VERSION 5.7 ;
  NOWIREEXTENSIONATPIN ON ;
  DIVIDERCHAR "/" ;
  BUSBITCHARS "[]" ;
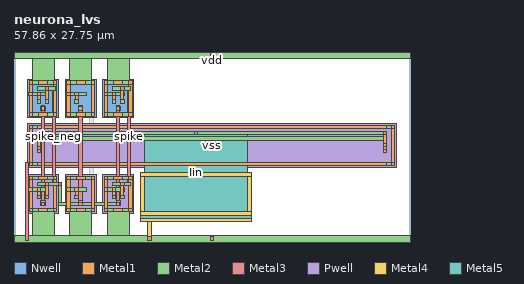
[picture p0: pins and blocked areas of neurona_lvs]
MACRO neurona_lvs
  CLASS BLOCK ;
  FOREIGN neurona_lvs ;
  ORIGIN 2.000 4.200 ;
  SIZE 57.860 BY 27.750 ;
  PIN vdd
    ANTENNADIFFAREA 18.719999 ;
    PORT
      LAYER Nwell ;
        RECT 0.000 13.950 4.490 19.550 ;
        RECT 5.490 13.950 9.980 19.550 ;
        RECT 10.980 13.950 15.470 19.550 ;
      LAYER Metal1 ;
        RECT 0.230 18.840 0.730 19.340 ;
        RECT 1.595 18.840 2.895 19.340 ;
        RECT 3.760 18.840 4.260 19.340 ;
        RECT 0.230 17.645 0.690 18.840 ;
        RECT 0.190 17.145 0.690 17.645 ;
        RECT 1.400 17.145 1.900 17.645 ;
        RECT 0.230 14.660 0.690 17.145 ;
        RECT 1.420 16.595 1.880 17.145 ;
        RECT 1.400 16.095 1.900 16.595 ;
        RECT 3.800 14.660 4.260 18.840 ;
        RECT 5.720 18.840 6.220 19.340 ;
        RECT 7.085 18.840 8.385 19.340 ;
        RECT 9.250 18.840 9.750 19.340 ;
        RECT 5.720 17.645 6.180 18.840 ;
        RECT 5.680 17.145 6.180 17.645 ;
        RECT 6.890 17.145 7.390 17.645 ;
        RECT 0.230 14.160 0.730 14.660 ;
        RECT 1.595 14.160 2.895 14.660 ;
        RECT 3.760 14.160 4.260 14.660 ;
        RECT 5.720 14.660 6.180 17.145 ;
        RECT 6.910 16.595 7.370 17.145 ;
        RECT 6.890 16.095 7.390 16.595 ;
        RECT 9.290 14.660 9.750 18.840 ;
        RECT 11.210 18.840 11.710 19.340 ;
        RECT 12.575 18.840 13.875 19.340 ;
        RECT 14.740 18.840 15.240 19.340 ;
        RECT 11.210 17.645 11.670 18.840 ;
        RECT 11.170 17.145 11.670 17.645 ;
        RECT 12.380 17.145 12.880 17.645 ;
        RECT 5.720 14.160 6.220 14.660 ;
        RECT 7.085 14.160 8.385 14.660 ;
        RECT 9.250 14.160 9.750 14.660 ;
        RECT 11.210 14.660 11.670 17.145 ;
        RECT 12.400 16.595 12.860 17.145 ;
        RECT 12.380 16.095 12.880 16.595 ;
        RECT 14.780 14.660 15.240 18.840 ;
        RECT 11.210 14.160 11.710 14.660 ;
        RECT 12.575 14.160 13.875 14.660 ;
        RECT 14.740 14.160 15.240 14.660 ;
      LAYER Metal2 ;
        RECT -2.000 22.550 55.860 23.550 ;
        RECT 0.640 19.340 3.850 22.550 ;
        RECT 6.130 19.340 9.340 22.550 ;
        RECT 11.620 19.340 14.830 22.550 ;
        RECT 0.230 18.840 4.260 19.340 ;
        RECT 5.720 18.840 9.750 19.340 ;
        RECT 11.210 18.840 15.240 19.340 ;
        RECT 0.190 17.145 3.090 17.645 ;
        RECT 5.680 17.145 8.580 17.645 ;
        RECT 11.170 17.145 14.070 17.645 ;
        RECT 1.400 16.095 1.900 16.595 ;
        RECT 6.890 16.095 7.390 16.595 ;
        RECT 12.380 16.095 12.880 16.595 ;
        RECT 0.230 14.160 4.260 14.660 ;
        RECT 5.720 14.160 9.750 14.660 ;
        RECT 11.210 14.160 15.240 14.660 ;
      LAYER Metal3 ;
        RECT 26.680 22.800 27.180 23.300 ;
    END
  END vdd
  PIN vss
    ANTENNADIFFAREA 61.496399 ;
    PORT
      LAYER Pwell ;
        RECT 0.000 6.725 53.860 13.075 ;
        RECT 0.000 0.000 4.490 5.600 ;
        RECT 5.490 0.000 9.980 5.600 ;
        RECT 10.980 0.000 15.470 5.600 ;
      LAYER Metal1 ;
        RECT 0.230 12.365 0.730 12.865 ;
        RECT 1.480 12.365 52.380 12.865 ;
        RECT 53.130 12.365 53.630 12.865 ;
        RECT 0.230 11.175 0.690 12.365 ;
        RECT 0.190 10.675 0.690 11.175 ;
        RECT 1.400 10.675 1.900 11.175 ;
        RECT 0.230 7.435 0.690 10.675 ;
        RECT 1.420 9.750 1.880 10.675 ;
        RECT 1.400 9.250 1.900 9.750 ;
        RECT 1.420 8.875 1.880 9.250 ;
        RECT 53.170 7.435 53.630 12.365 ;
        RECT 0.230 6.935 0.730 7.435 ;
        RECT 1.480 6.935 52.380 7.435 ;
        RECT 53.130 6.935 53.630 7.435 ;
        RECT 0.230 4.890 0.730 5.390 ;
        RECT 1.595 4.890 2.895 5.390 ;
        RECT 3.760 4.890 4.260 5.390 ;
        RECT 0.230 3.695 0.690 4.890 ;
        RECT 0.190 3.195 0.690 3.695 ;
        RECT 1.400 3.195 1.900 3.695 ;
        RECT 0.230 0.710 0.690 3.195 ;
        RECT 1.420 2.645 1.880 3.195 ;
        RECT 1.400 2.145 1.900 2.645 ;
        RECT 3.800 0.710 4.260 4.890 ;
        RECT 5.720 4.890 6.220 5.390 ;
        RECT 7.085 4.890 8.385 5.390 ;
        RECT 9.250 4.890 9.750 5.390 ;
        RECT 5.720 3.695 6.180 4.890 ;
        RECT 5.680 3.195 6.180 3.695 ;
        RECT 6.890 3.195 7.390 3.695 ;
        RECT 0.230 0.210 0.730 0.710 ;
        RECT 1.595 0.210 2.895 0.710 ;
        RECT 3.760 0.210 4.260 0.710 ;
        RECT 5.720 0.710 6.180 3.195 ;
        RECT 6.910 2.645 7.370 3.195 ;
        RECT 6.890 2.145 7.390 2.645 ;
        RECT 9.290 0.710 9.750 4.890 ;
        RECT 11.210 4.890 11.710 5.390 ;
        RECT 12.575 4.890 13.875 5.390 ;
        RECT 14.740 4.890 15.240 5.390 ;
        RECT 11.210 3.695 11.670 4.890 ;
        RECT 11.170 3.195 11.670 3.695 ;
        RECT 12.380 3.195 12.880 3.695 ;
        RECT 5.720 0.210 6.220 0.710 ;
        RECT 7.085 0.210 8.385 0.710 ;
        RECT 9.250 0.210 9.750 0.710 ;
        RECT 11.210 0.710 11.670 3.195 ;
        RECT 12.400 2.645 12.860 3.195 ;
        RECT 12.380 2.145 12.880 2.645 ;
        RECT 14.780 0.710 15.240 4.890 ;
        RECT 11.210 0.210 11.710 0.710 ;
        RECT 12.575 0.210 13.875 0.710 ;
        RECT 14.740 0.210 15.240 0.710 ;
      LAYER Metal2 ;
        RECT 0.230 12.365 53.630 12.865 ;
        RECT 0.190 10.675 52.460 11.175 ;
        RECT 1.400 8.875 1.900 10.125 ;
        RECT -0.360 6.935 53.630 7.435 ;
        RECT 0.230 4.890 4.260 5.390 ;
        RECT 5.720 4.890 9.750 5.390 ;
        RECT 11.210 4.890 15.240 5.390 ;
        RECT 0.190 3.195 3.090 3.695 ;
        RECT 5.680 3.195 8.580 3.695 ;
        RECT 11.170 3.195 14.070 3.695 ;
        RECT 1.400 2.145 1.900 2.645 ;
        RECT 6.890 2.145 7.390 2.645 ;
        RECT 12.380 2.145 12.880 2.645 ;
        RECT 0.230 0.210 4.260 0.710 ;
        RECT 5.720 0.210 9.750 0.710 ;
        RECT 11.210 0.210 15.240 0.710 ;
        RECT 0.640 -3.200 3.850 0.210 ;
        RECT 6.130 -3.200 9.340 0.210 ;
        RECT 11.620 -3.200 14.830 0.210 ;
        RECT -2.000 -4.200 55.860 -3.200 ;
      LAYER Metal3 ;
        RECT -0.360 -3.950 0.140 7.435 ;
        RECT 17.520 -3.950 18.020 -3.450 ;
        RECT 26.680 -3.950 27.180 -3.450 ;
      LAYER Metal4 ;
        RECT 16.470 5.300 32.670 5.900 ;
        RECT 16.470 0.300 17.070 5.300 ;
        RECT 32.070 0.300 32.670 5.300 ;
        RECT 16.470 -1.200 32.670 0.300 ;
        RECT 17.520 -3.950 18.020 -1.200 ;
      LAYER Metal5 ;
        RECT 16.470 -0.800 32.670 -0.300 ;
    END
  END vss
  PIN spike
    ANTENNADIFFAREA 0.600000 ;
    PORT
      LAYER Metal1 ;
        RECT 13.570 17.945 14.070 18.445 ;
        RECT 13.590 16.595 14.050 17.945 ;
        RECT 13.570 16.095 14.070 16.595 ;
        RECT 13.570 3.995 14.070 4.495 ;
        RECT 13.590 2.645 14.050 3.995 ;
        RECT 13.570 2.145 14.070 2.645 ;
      LAYER Metal2 ;
        RECT 12.380 17.945 15.070 18.445 ;
        RECT 13.570 16.095 14.070 16.595 ;
        RECT 12.380 3.995 15.070 4.495 ;
        RECT 13.570 2.145 14.070 2.645 ;
      LAYER Metal3 ;
        RECT 13.570 17.945 14.070 18.445 ;
        RECT 14.570 3.995 15.070 18.445 ;
    END
  END spike
  PIN spike_neg
    ANTENNAGATEAREA 1.260000 ;
    ANTENNADIFFAREA 0.600000 ;
    PORT
      LAYER Metal1 ;
        RECT 2.590 17.945 3.090 18.445 ;
        RECT 2.610 16.595 3.070 17.945 ;
        RECT 2.590 16.095 3.090 16.595 ;
        RECT 7.485 15.055 7.985 15.555 ;
        RECT 12.975 15.055 13.475 15.555 ;
        RECT 2.590 3.995 3.090 4.495 ;
        RECT 2.610 2.645 3.070 3.995 ;
        RECT 2.590 2.145 3.090 2.645 ;
        RECT 7.485 1.105 7.985 1.605 ;
        RECT 12.975 1.105 13.475 1.605 ;
      LAYER Metal2 ;
        RECT 1.400 17.945 4.090 18.445 ;
        RECT 2.590 16.095 3.090 16.595 ;
        RECT 7.485 15.555 7.985 15.805 ;
        RECT 12.975 15.555 13.475 15.805 ;
        RECT 7.420 15.055 8.050 15.555 ;
        RECT 12.910 15.055 13.540 15.555 ;
        RECT 1.400 3.995 4.940 4.495 ;
        RECT 2.590 2.145 3.090 2.645 ;
        RECT 4.440 1.605 4.940 3.995 ;
        RECT 7.420 1.605 8.050 1.855 ;
        RECT 12.910 1.605 13.540 1.855 ;
        RECT 4.440 1.105 13.540 1.605 ;
      LAYER Metal3 ;
        RECT 2.590 17.945 3.090 18.445 ;
        RECT 3.590 3.995 4.090 18.445 ;
        RECT 4.440 3.995 4.940 4.495 ;
        RECT 7.485 1.355 7.985 15.805 ;
        RECT 12.975 1.355 13.475 15.805 ;
    END
  END spike_neg
  PIN Iin
    ANTENNAGATEAREA 0.630000 ;
    ANTENNADIFFAREA 0.750000 ;
    PORT
      LAYER Metal1 ;
        RECT 1.995 15.055 2.495 15.555 ;
        RECT 51.960 11.475 52.460 11.975 ;
        RECT 51.980 9.750 52.440 11.475 ;
        RECT 51.960 9.250 52.460 9.750 ;
        RECT 51.980 8.875 52.440 9.250 ;
        RECT 1.995 1.105 2.495 1.605 ;
      LAYER Metal2 ;
        RECT 1.995 15.555 2.495 15.805 ;
        RECT 1.930 15.055 2.560 15.555 ;
        RECT 1.995 11.975 2.495 12.005 ;
        RECT 1.400 11.475 52.460 11.975 ;
        RECT 51.960 8.875 52.460 10.125 ;
        RECT 1.930 1.105 2.560 1.855 ;
      LAYER Metal3 ;
        RECT 1.995 1.355 2.495 15.805 ;
        RECT 24.320 11.475 24.820 11.975 ;
        RECT 51.960 11.475 52.460 11.975 ;
      LAYER Metal4 ;
        RECT 24.320 11.475 24.820 11.975 ;
      LAYER Metal5 ;
        RECT 24.320 11.475 24.820 11.975 ;
        RECT 17.070 0.300 32.070 11.475 ;
    END
  END Iin
  OBS
      LAYER Metal1 ;
        RECT 8.080 17.945 8.580 18.445 ;
        RECT 8.100 16.595 8.560 17.945 ;
        RECT 8.080 16.095 8.580 16.595 ;
        RECT 2.280 7.830 2.780 8.330 ;
        RECT 3.080 7.830 3.580 8.330 ;
        RECT 3.880 7.830 4.380 8.330 ;
        RECT 4.680 7.830 5.180 8.330 ;
        RECT 5.480 7.830 5.980 8.330 ;
        RECT 6.280 7.830 6.780 8.330 ;
        RECT 7.080 7.830 7.580 8.330 ;
        RECT 7.880 7.830 8.380 8.330 ;
        RECT 8.680 7.830 9.180 8.330 ;
        RECT 9.480 7.830 9.980 8.330 ;
        RECT 10.280 7.830 10.780 8.330 ;
        RECT 11.080 7.830 11.580 8.330 ;
        RECT 11.880 7.830 12.380 8.330 ;
        RECT 12.680 7.830 13.180 8.330 ;
        RECT 13.480 7.830 13.980 8.330 ;
        RECT 14.280 7.830 14.780 8.330 ;
        RECT 15.080 7.830 15.580 8.330 ;
        RECT 15.880 7.830 16.380 8.330 ;
        RECT 16.680 7.830 17.180 8.330 ;
        RECT 17.480 7.830 17.980 8.330 ;
        RECT 18.280 7.830 18.780 8.330 ;
        RECT 19.080 7.830 19.580 8.330 ;
        RECT 19.880 7.830 20.380 8.330 ;
        RECT 20.680 7.830 21.180 8.330 ;
        RECT 21.480 7.830 21.980 8.330 ;
        RECT 22.280 7.830 22.780 8.330 ;
        RECT 23.080 7.830 23.580 8.330 ;
        RECT 23.880 7.830 24.380 8.330 ;
        RECT 24.680 7.830 25.180 8.330 ;
        RECT 25.480 7.830 25.980 8.330 ;
        RECT 26.280 7.830 26.780 8.330 ;
        RECT 27.080 7.830 27.580 8.330 ;
        RECT 27.880 7.830 28.380 8.330 ;
        RECT 28.680 7.830 29.180 8.330 ;
        RECT 29.480 7.830 29.980 8.330 ;
        RECT 30.280 7.830 30.780 8.330 ;
        RECT 31.080 7.830 31.580 8.330 ;
        RECT 31.880 7.830 32.380 8.330 ;
        RECT 32.680 7.830 33.180 8.330 ;
        RECT 33.480 7.830 33.980 8.330 ;
        RECT 34.280 7.830 34.780 8.330 ;
        RECT 35.080 7.830 35.580 8.330 ;
        RECT 35.880 7.830 36.380 8.330 ;
        RECT 36.680 7.830 37.180 8.330 ;
        RECT 37.480 7.830 37.980 8.330 ;
        RECT 38.280 7.830 38.780 8.330 ;
        RECT 39.080 7.830 39.580 8.330 ;
        RECT 39.880 7.830 40.380 8.330 ;
        RECT 40.680 7.830 41.180 8.330 ;
        RECT 41.480 7.830 41.980 8.330 ;
        RECT 42.280 7.830 42.780 8.330 ;
        RECT 43.080 7.830 43.580 8.330 ;
        RECT 43.880 7.830 44.380 8.330 ;
        RECT 44.680 7.830 45.180 8.330 ;
        RECT 45.480 7.830 45.980 8.330 ;
        RECT 46.280 7.830 46.780 8.330 ;
        RECT 47.080 7.830 47.580 8.330 ;
        RECT 47.880 7.830 48.380 8.330 ;
        RECT 48.680 7.830 49.180 8.330 ;
        RECT 49.480 7.830 49.980 8.330 ;
        RECT 50.280 7.830 50.780 8.330 ;
        RECT 51.080 7.830 51.580 8.330 ;
        RECT 8.080 3.995 8.580 4.495 ;
        RECT 8.100 2.645 8.560 3.995 ;
        RECT 8.080 2.145 8.580 2.645 ;
      LAYER Metal2 ;
        RECT 6.890 17.945 9.580 18.445 ;
        RECT 8.080 16.095 8.580 16.595 ;
        RECT 1.930 7.830 51.930 8.330 ;
        RECT 6.890 3.995 9.580 4.495 ;
        RECT 8.080 2.145 8.580 2.645 ;
      LAYER Metal3 ;
        RECT 9.080 8.330 9.580 18.445 ;
        RECT 9.080 7.830 9.680 8.330 ;
        RECT 9.080 3.995 9.580 7.830 ;
  END
END neurona_lvs
END LIBRARY

